VERSION 5.7 ;
  NOWIREEXTENSIONATPIN ON ;
  DIVIDERCHAR "/" ;
  BUSBITCHARS "[]" ;
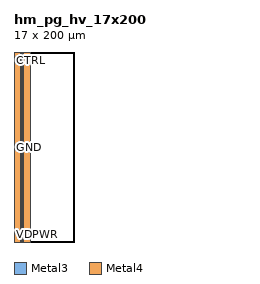
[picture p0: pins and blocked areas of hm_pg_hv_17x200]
MACRO hm_pg_hv_17x200
  CLASS BLOCK ;
  FOREIGN hm_pg_hv_17x200 ;
  ORIGIN 0.000 0.000 ;
  SIZE 17.000 BY 200.000 ;
  PIN CTRL
    DIRECTION INPUT ;
    USE SIGNAL ;
    ANTENNAGATEAREA 0.390000 ;
    PORT
      LAYER Metal3 ;
        RECT 0.000 199.500 17.000 200.000 ;
    END
  END CTRL
  PIN VAPWR
    DIRECTION INOUT ;
    USE POWER ;
    PORT
      LAYER Metal4 ;
        RECT 0.000 0.000 7.000 200.000 ;
    END
  END VAPWR
  PIN GND
    DIRECTION INOUT ;
    USE GROUND ;
    PORT
      LAYER Metal4 ;
        RECT 7.320 0.000 8.340 200.000 ;
    END
  END GND
  PIN VDPWR
    DIRECTION INOUT ;
    USE POWER ;
    PORT
      LAYER Metal4 ;
        RECT 8.660 0.000 9.680 200.000 ;
    END
  END VDPWR
  PIN GPWR
    DIRECTION INOUT ;
    USE POWER ;
    PORT
      LAYER Metal4 ;
        RECT 10.000 0.000 17.000 200.000 ;
    END
  END GPWR
  OBS
      LAYER GatPoly ;
        RECT 0.030 0.240 16.700 197.750 ;
      LAYER Metal1 ;
        RECT 0.000 0.240 16.700 198.260 ;
      LAYER Metal2 ;
        RECT 0.000 0.000 15.850 200.000 ;
      LAYER Metal3 ;
        RECT 0.000 0.000 17.000 197.550 ;
  END
END hm_pg_hv_17x200
END LIBRARY

